VERSION 5.7 ;
  NOWIREEXTENSIONATPIN ON ;
  DIVIDERCHAR "/" ;
  BUSBITCHARS "[]" ;
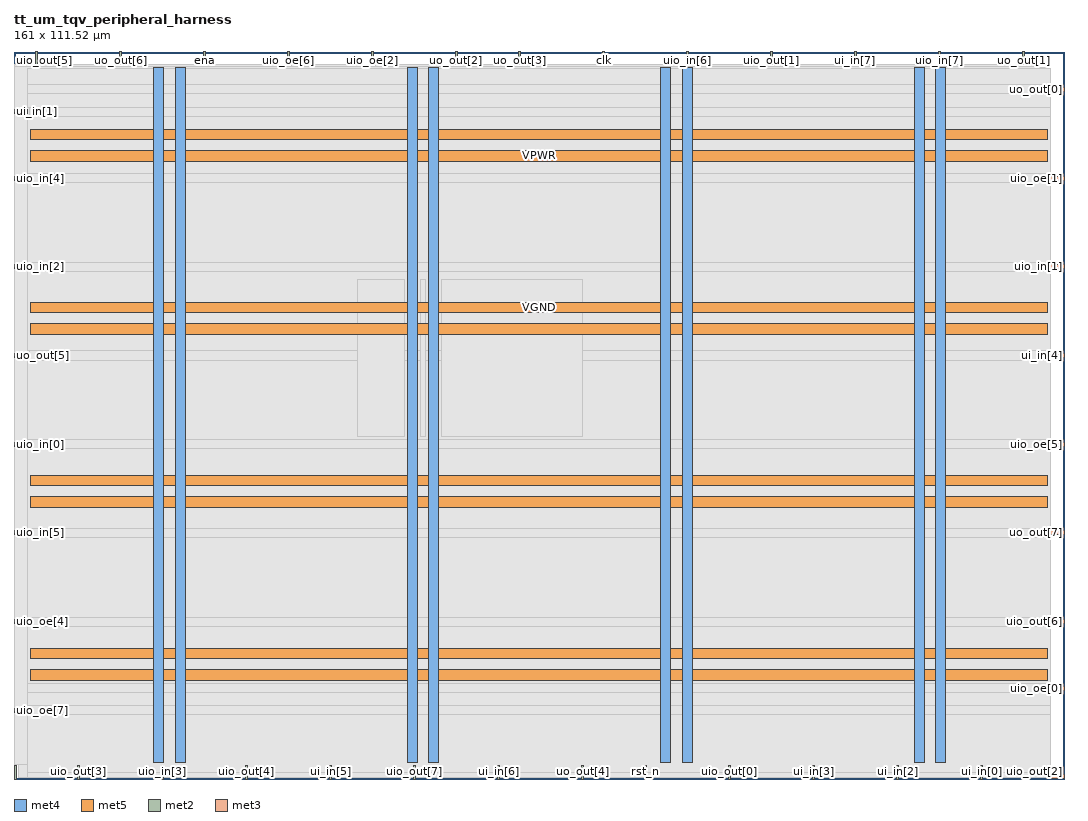
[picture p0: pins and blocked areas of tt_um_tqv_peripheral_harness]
MACRO tt_um_tqv_peripheral_harness
  CLASS BLOCK ;
  FOREIGN tt_um_tqv_peripheral_harness ;
  ORIGIN 0.000 0.000 ;
  SIZE 161.000 BY 111.520 ;
  PIN VGND
    DIRECTION INOUT ;
    USE GROUND ;
    PORT
      LAYER met4 ;
        RECT 24.695 2.480 26.295 109.040 ;
    END
    PORT
      LAYER met4 ;
        RECT 63.565 2.480 65.165 109.040 ;
    END
    PORT
      LAYER met4 ;
        RECT 102.435 2.480 104.035 109.040 ;
    END
    PORT
      LAYER met4 ;
        RECT 141.305 2.480 142.905 109.040 ;
    END
    PORT
      LAYER met5 ;
        RECT 2.520 18.480 158.480 20.080 ;
    END
    PORT
      LAYER met5 ;
        RECT 2.520 45.000 158.480 46.600 ;
    END
    PORT
      LAYER met5 ;
        RECT 2.520 71.520 158.480 73.120 ;
    END
    PORT
      LAYER met5 ;
        RECT 2.520 98.040 158.480 99.640 ;
    END
  END VGND
  PIN VPWR
    DIRECTION INOUT ;
    USE POWER ;
    PORT
      LAYER met4 ;
        RECT 21.395 2.480 22.995 109.040 ;
    END
    PORT
      LAYER met4 ;
        RECT 60.265 2.480 61.865 109.040 ;
    END
    PORT
      LAYER met4 ;
        RECT 99.135 2.480 100.735 109.040 ;
    END
    PORT
      LAYER met4 ;
        RECT 138.005 2.480 139.605 109.040 ;
    END
    PORT
      LAYER met5 ;
        RECT 2.520 15.180 158.480 16.780 ;
    END
    PORT
      LAYER met5 ;
        RECT 2.520 41.700 158.480 43.300 ;
    END
    PORT
      LAYER met5 ;
        RECT 2.520 68.220 158.480 69.820 ;
    END
    PORT
      LAYER met5 ;
        RECT 2.520 94.740 158.480 96.340 ;
    END
  END VPWR
  PIN clk
    DIRECTION INPUT ;
    USE SIGNAL ;
    ANTENNAGATEAREA 0.852000 ;
    PORT
      LAYER met2 ;
        RECT 90.250 109.520 90.530 111.520 ;
    END
  END clk
  PIN ena
    DIRECTION INPUT ;
    USE SIGNAL ;
    PORT
      LAYER met2 ;
        RECT 29.070 109.520 29.350 111.520 ;
    END
  END ena
  PIN rst_n
    DIRECTION INPUT ;
    USE SIGNAL ;
    ANTENNAGATEAREA 0.196500 ;
    PORT
      LAYER met2 ;
        RECT 96.690 0.000 96.970 2.000 ;
    END
  END rst_n
  PIN ui_in[0]
    DIRECTION INPUT ;
    USE SIGNAL ;
    PORT
      LAYER met2 ;
        RECT 148.210 0.000 148.490 2.000 ;
    END
  END ui_in[0]
  PIN ui_in[1]
    DIRECTION INPUT ;
    USE SIGNAL ;
    PORT
      LAYER met3 ;
        RECT 0.000 102.040 2.000 102.640 ;
    END
  END ui_in[1]
  PIN ui_in[2]
    DIRECTION INPUT ;
    USE SIGNAL ;
    PORT
      LAYER met2 ;
        RECT 135.330 0.000 135.610 2.000 ;
    END
  END ui_in[2]
  PIN ui_in[3]
    DIRECTION INPUT ;
    USE SIGNAL ;
    PORT
      LAYER met2 ;
        RECT 122.450 0.000 122.730 2.000 ;
    END
  END ui_in[3]
  PIN ui_in[4]
    DIRECTION INPUT ;
    USE SIGNAL ;
    PORT
      LAYER met3 ;
        RECT 159.000 64.640 161.000 65.240 ;
    END
  END ui_in[4]
  PIN ui_in[5]
    DIRECTION INPUT ;
    USE SIGNAL ;
    PORT
      LAYER met2 ;
        RECT 48.390 0.000 48.670 2.000 ;
    END
  END ui_in[5]
  PIN ui_in[6]
    DIRECTION INPUT ;
    USE SIGNAL ;
    PORT
      LAYER met2 ;
        RECT 74.150 0.000 74.430 2.000 ;
    END
  END ui_in[6]
  PIN ui_in[7]
    DIRECTION INPUT ;
    USE SIGNAL ;
    PORT
      LAYER met2 ;
        RECT 128.890 109.520 129.170 111.520 ;
    END
  END ui_in[7]
  PIN uio_in[0]
    DIRECTION INPUT ;
    USE SIGNAL ;
    PORT
      LAYER met3 ;
        RECT 0.000 51.040 2.000 51.640 ;
    END
  END uio_in[0]
  PIN uio_in[1]
    DIRECTION INPUT ;
    USE SIGNAL ;
    PORT
      LAYER met3 ;
        RECT 159.000 78.240 161.000 78.840 ;
    END
  END uio_in[1]
  PIN uio_in[2]
    DIRECTION INPUT ;
    USE SIGNAL ;
    PORT
      LAYER met3 ;
        RECT 0.000 78.240 2.000 78.840 ;
    END
  END uio_in[2]
  PIN uio_in[3]
    DIRECTION INPUT ;
    USE SIGNAL ;
    PORT
      LAYER met2 ;
        RECT 22.630 0.000 22.910 2.000 ;
    END
  END uio_in[3]
  PIN uio_in[4]
    DIRECTION INPUT ;
    USE SIGNAL ;
    ANTENNAGATEAREA 0.196500 ;
    PORT
      LAYER met3 ;
        RECT 0.000 91.840 2.000 92.440 ;
    END
  END uio_in[4]
  PIN uio_in[5]
    DIRECTION INPUT ;
    USE SIGNAL ;
    ANTENNAGATEAREA 0.196500 ;
    PORT
      LAYER met3 ;
        RECT 0.000 37.440 2.000 38.040 ;
    END
  END uio_in[5]
  PIN uio_in[6]
    DIRECTION INPUT ;
    USE SIGNAL ;
    ANTENNAGATEAREA 0.196500 ;
    PORT
      LAYER met2 ;
        RECT 103.130 109.520 103.410 111.520 ;
    END
  END uio_in[6]
  PIN uio_in[7]
    DIRECTION INPUT ;
    USE SIGNAL ;
    PORT
      LAYER met2 ;
        RECT 141.770 109.520 142.050 111.520 ;
    END
  END uio_in[7]
  PIN uio_oe[0]
    DIRECTION OUTPUT TRISTATE ;
    USE SIGNAL ;
    PORT
      LAYER met3 ;
        RECT 159.000 13.640 161.000 14.240 ;
    END
  END uio_oe[0]
  PIN uio_oe[1]
    DIRECTION OUTPUT TRISTATE ;
    USE SIGNAL ;
    PORT
      LAYER met3 ;
        RECT 159.000 91.840 161.000 92.440 ;
    END
  END uio_oe[1]
  PIN uio_oe[2]
    DIRECTION OUTPUT TRISTATE ;
    USE SIGNAL ;
    PORT
      LAYER met2 ;
        RECT 54.830 109.520 55.110 111.520 ;
    END
  END uio_oe[2]
  PIN uio_oe[3]
    DIRECTION OUTPUT TRISTATE ;
    USE SIGNAL ;
    PORT
      LAYER met2 ;
        RECT 0.090 0.000 0.370 2.000 ;
    END
  END uio_oe[3]
  PIN uio_oe[4]
    DIRECTION OUTPUT TRISTATE ;
    USE SIGNAL ;
    PORT
      LAYER met3 ;
        RECT 0.000 23.840 2.000 24.440 ;
    END
  END uio_oe[4]
  PIN uio_oe[5]
    DIRECTION OUTPUT TRISTATE ;
    USE SIGNAL ;
    PORT
      LAYER met3 ;
        RECT 159.000 51.040 161.000 51.640 ;
    END
  END uio_oe[5]
  PIN uio_oe[6]
    DIRECTION OUTPUT TRISTATE ;
    USE SIGNAL ;
    PORT
      LAYER met2 ;
        RECT 41.950 109.520 42.230 111.520 ;
    END
  END uio_oe[6]
  PIN uio_oe[7]
    DIRECTION OUTPUT TRISTATE ;
    USE SIGNAL ;
    PORT
      LAYER met3 ;
        RECT 0.000 10.240 2.000 10.840 ;
    END
  END uio_oe[7]
  PIN uio_out[0]
    DIRECTION OUTPUT TRISTATE ;
    USE SIGNAL ;
    PORT
      LAYER met2 ;
        RECT 109.570 0.000 109.850 2.000 ;
    END
  END uio_out[0]
  PIN uio_out[1]
    DIRECTION OUTPUT TRISTATE ;
    USE SIGNAL ;
    PORT
      LAYER met2 ;
        RECT 116.010 109.520 116.290 111.520 ;
    END
  END uio_out[1]
  PIN uio_out[2]
    DIRECTION OUTPUT TRISTATE ;
    USE SIGNAL ;
    PORT
      LAYER met3 ;
        RECT 159.000 0.040 161.000 0.640 ;
    END
  END uio_out[2]
  PIN uio_out[3]
    DIRECTION OUTPUT TRISTATE ;
    USE SIGNAL ;
    ANTENNADIFFAREA 0.445500 ;
    PORT
      LAYER met2 ;
        RECT 9.750 0.000 10.030 2.000 ;
    END
  END uio_out[3]
  PIN uio_out[4]
    DIRECTION OUTPUT TRISTATE ;
    USE SIGNAL ;
    PORT
      LAYER met2 ;
        RECT 35.510 0.000 35.790 2.000 ;
    END
  END uio_out[4]
  PIN uio_out[5]
    DIRECTION OUTPUT TRISTATE ;
    USE SIGNAL ;
    PORT
      LAYER met2 ;
        RECT 3.310 109.520 3.590 111.520 ;
    END
  END uio_out[5]
  PIN uio_out[6]
    DIRECTION OUTPUT TRISTATE ;
    USE SIGNAL ;
    PORT
      LAYER met3 ;
        RECT 159.000 23.840 161.000 24.440 ;
    END
  END uio_out[6]
  PIN uio_out[7]
    DIRECTION OUTPUT TRISTATE ;
    USE SIGNAL ;
    PORT
      LAYER met2 ;
        RECT 61.270 0.000 61.550 2.000 ;
    END
  END uio_out[7]
  PIN uo_out[0]
    DIRECTION OUTPUT TRISTATE ;
    USE SIGNAL ;
    ANTENNADIFFAREA 0.445500 ;
    PORT
      LAYER met3 ;
        RECT 159.000 105.440 161.000 106.040 ;
    END
  END uo_out[0]
  PIN uo_out[1]
    DIRECTION OUTPUT TRISTATE ;
    USE SIGNAL ;
    ANTENNADIFFAREA 0.445500 ;
    PORT
      LAYER met2 ;
        RECT 154.650 109.520 154.930 111.520 ;
    END
  END uo_out[1]
  PIN uo_out[2]
    DIRECTION OUTPUT TRISTATE ;
    USE SIGNAL ;
    ANTENNADIFFAREA 0.445500 ;
    PORT
      LAYER met2 ;
        RECT 67.710 109.520 67.990 111.520 ;
    END
  END uo_out[2]
  PIN uo_out[3]
    DIRECTION OUTPUT TRISTATE ;
    USE SIGNAL ;
    ANTENNADIFFAREA 0.445500 ;
    PORT
      LAYER met2 ;
        RECT 77.370 109.520 77.650 111.520 ;
    END
  END uo_out[3]
  PIN uo_out[4]
    DIRECTION OUTPUT TRISTATE ;
    USE SIGNAL ;
    ANTENNADIFFAREA 0.445500 ;
    PORT
      LAYER met2 ;
        RECT 87.030 0.000 87.310 2.000 ;
    END
  END uo_out[4]
  PIN uo_out[5]
    DIRECTION OUTPUT TRISTATE ;
    USE SIGNAL ;
    ANTENNADIFFAREA 0.445500 ;
    PORT
      LAYER met3 ;
        RECT 0.000 64.640 2.000 65.240 ;
    END
  END uo_out[5]
  PIN uo_out[6]
    DIRECTION OUTPUT TRISTATE ;
    USE SIGNAL ;
    ANTENNADIFFAREA 0.445500 ;
    PORT
      LAYER met2 ;
        RECT 16.190 109.520 16.470 111.520 ;
    END
  END uo_out[6]
  PIN uo_out[7]
    DIRECTION OUTPUT TRISTATE ;
    USE SIGNAL ;
    ANTENNADIFFAREA 0.445500 ;
    PORT
      LAYER met3 ;
        RECT 159.000 37.440 161.000 38.040 ;
    END
  END uo_out[7]
  OBS
      LAYER li1 ;
        RECT 2.760 2.635 158.240 108.885 ;
      LAYER met1 ;
        RECT 0.070 2.480 158.240 109.040 ;
      LAYER met2 ;
        RECT 0.100 109.240 3.030 109.520 ;
        RECT 3.870 109.240 15.910 109.520 ;
        RECT 16.750 109.240 28.790 109.520 ;
        RECT 29.630 109.240 41.670 109.520 ;
        RECT 42.510 109.240 54.550 109.520 ;
        RECT 55.390 109.240 67.430 109.520 ;
        RECT 68.270 109.240 77.090 109.520 ;
        RECT 77.930 109.240 89.970 109.520 ;
        RECT 90.810 109.240 102.850 109.520 ;
        RECT 103.690 109.240 115.730 109.520 ;
        RECT 116.570 109.240 128.610 109.520 ;
        RECT 129.450 109.240 141.490 109.520 ;
        RECT 142.330 109.240 154.370 109.520 ;
        RECT 155.210 109.240 156.770 109.520 ;
        RECT 0.100 2.280 156.770 109.240 ;
        RECT 0.650 0.155 9.470 2.280 ;
        RECT 10.310 0.155 22.350 2.280 ;
        RECT 23.190 0.155 35.230 2.280 ;
        RECT 36.070 0.155 48.110 2.280 ;
        RECT 48.950 0.155 60.990 2.280 ;
        RECT 61.830 0.155 73.870 2.280 ;
        RECT 74.710 0.155 86.750 2.280 ;
        RECT 87.590 0.155 96.410 2.280 ;
        RECT 97.250 0.155 109.290 2.280 ;
        RECT 110.130 0.155 122.170 2.280 ;
        RECT 123.010 0.155 135.050 2.280 ;
        RECT 135.890 0.155 147.930 2.280 ;
        RECT 148.770 0.155 156.770 2.280 ;
      LAYER met3 ;
        RECT 2.000 106.440 159.000 108.965 ;
        RECT 2.000 105.040 158.600 106.440 ;
        RECT 2.000 103.040 159.000 105.040 ;
        RECT 2.400 101.640 159.000 103.040 ;
        RECT 2.000 92.840 159.000 101.640 ;
        RECT 2.400 91.440 158.600 92.840 ;
        RECT 2.000 79.240 159.000 91.440 ;
        RECT 2.400 77.840 158.600 79.240 ;
        RECT 2.000 65.640 159.000 77.840 ;
        RECT 2.400 64.240 158.600 65.640 ;
        RECT 2.000 52.040 159.000 64.240 ;
        RECT 2.400 50.640 158.600 52.040 ;
        RECT 2.000 38.440 159.000 50.640 ;
        RECT 2.400 37.040 158.600 38.440 ;
        RECT 2.000 24.840 159.000 37.040 ;
        RECT 2.400 23.440 158.600 24.840 ;
        RECT 2.000 14.640 159.000 23.440 ;
        RECT 2.000 13.240 158.600 14.640 ;
        RECT 2.000 11.240 159.000 13.240 ;
        RECT 2.400 9.840 159.000 11.240 ;
        RECT 2.000 1.040 159.000 9.840 ;
        RECT 2.000 0.175 158.600 1.040 ;
      LAYER met4 ;
        RECT 52.735 52.535 59.865 76.665 ;
        RECT 62.265 52.535 63.165 76.665 ;
        RECT 65.565 52.535 87.105 76.665 ;
  END
END tt_um_tqv_peripheral_harness
END LIBRARY

